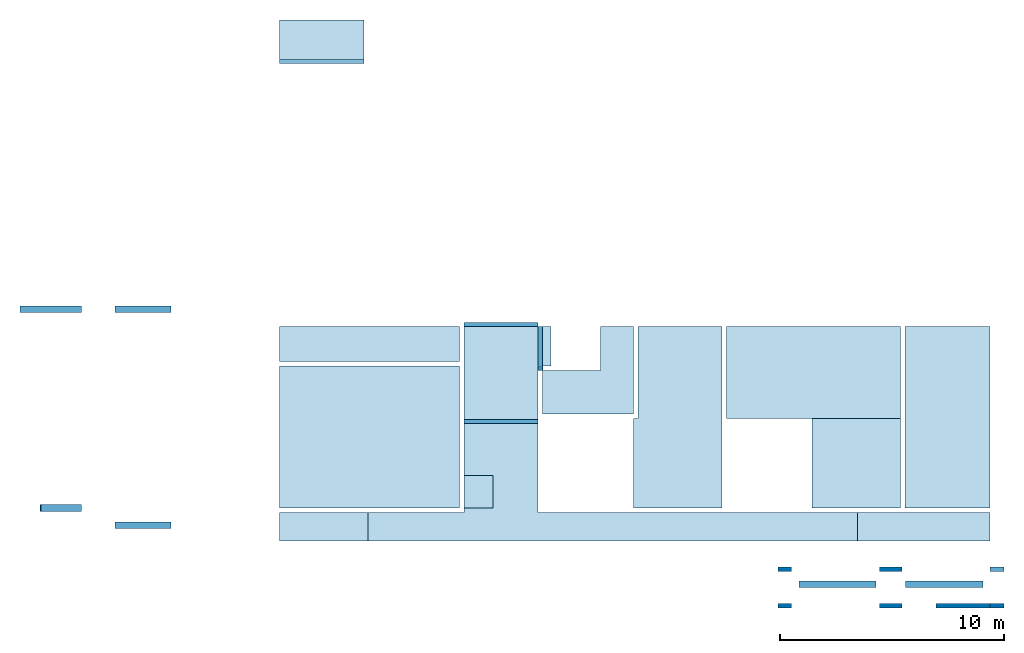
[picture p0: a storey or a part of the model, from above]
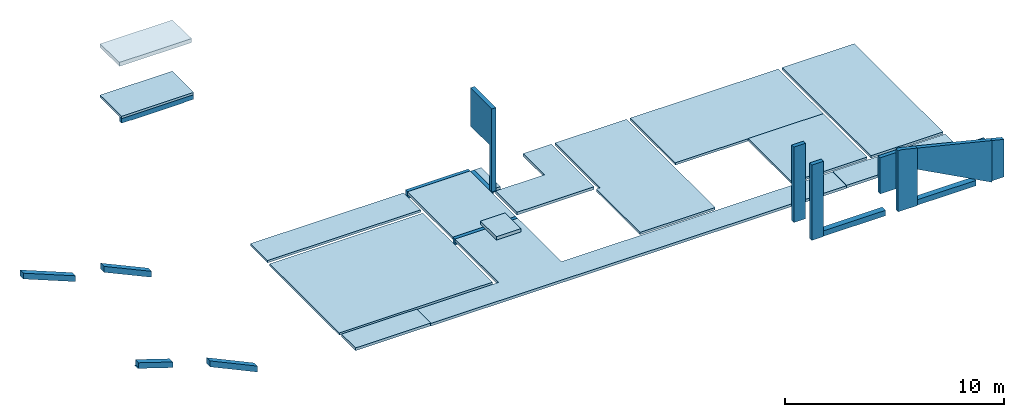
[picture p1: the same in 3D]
Properties of the parts of a building model (IFC2X3)

# File
Description: ViewDefinition [CoordinationView_V2.0]
File name: 20-10
Time: 2021-09-02T08:59:20
Written by: The EXPRESS Data Manager Version 5.02.0100.07 : 28 Aug 2013
Made in: 20200210_1400(x64) - Exporter 20.2.12.1 - Alternate UI 20.2.12.1
Comment: STEP Physical File produced by: The EXPRESS Data Manager Version 5.02.0100.07 : 28 Aug 2013 * Module: EDMstepFileFactory/EDMstandAlone * Creation date: Thu Sep 02 08:59:20 2021 * Host: KAWESQAR * Database: C:\Users\MANONB~1\AppData\Local\Temp\62fa37c4-7dab-49d4-8f40-0b2dbcf1714f\3ce987a9-b15d-487f-94de-988076b2c18d\ifc * Database version: 5507 * Database creation date: Thu Sep 02 08:59:12 2021 * Schema: IFC2X3 * Model: DataRepository.ifc * Model creation date: Thu Sep 02 08:59:13 2021 * Header model: DataRepository.ifc_HeaderModel * Header model creation date: Thu Sep 02 08:59:13 2021 * EDMuser: sdai-user * EDMgroup: sdai-group * License ID and type: 5605 : Permanent license. Expiry date: * EDMstepFileFactory options: 020000

# IfcProject, 20-10
LongName: OPERATION

# IfcSite, Default
RefLatitude: 48, 51, 57, 604064; RefLongitude: 2, 19, 58, 799800; RefElevation: 0 m

# IfcBuilding
Pset_BuildingCommon - NumberOfStoreys: 9
Pset_ProductRequirements - Category: Project Information

# IfcBuildingStorey: Niveau:911002-NIV_nom.topo (9)
Pset_ProductRequirements - Category: Levels
Name | LongName | Elevation (m) | Pset_AirSideSystemInformation, Name = Pset_ProductRequirements, Name
S02 | S02 | -5.05 | Fondations - Vue en plan
S02 | S02 | -4.68 | STR-SS01 Brut
S02 | S02 | -4.62 | STR-SS01 Fini
S01 | S01 | -0.4 | STR-FOND RDC
S01 | S01 | -0.06 | STR-RDC Brut
S01 | S01 | 0 | STR-RDC Fini
01 | 01 | 4.27 | STR-R+1
01 | 01 | 7.55 | STR-R+2
01 | 01 | 10.65 | STR-R+3

# IfcBeam: 16x23ht (2)
In: S01
Type - PredefinedType: BEAM; Material: Béton, coulé sur place gris
Type - Pset_BeamCommon - IsExternal: no; Reference: 16x23ht
Type - Pset_ProductRequirements - Category: Structural Framing
Type - Pset_QuantityTakeOff - Reference: 16x23ht
Type - Pset_ReinforcementBarPitchOfBeam - Reference: 16x23ht
Pset_BeamCommon - Slope: 0 deg; Span: 4.4883 m
Pset_QuantityTakeOff - sets with these values: 2
Name (II-Poutre rectangulaire - Béton:16x23ht:...)
7692531
7692542

# IfcBeam: 16x23ht (9)
In: S01
Type - PredefinedType: BEAM
Type - Pset_BeamCommon - IsExternal: no; Reference: 16x23ht
Type - Pset_ProductRequirements - Category: Structural Framing
Type - Pset_QuantityTakeOff - Reference: 16x23ht
Type - Pset_ReinforcementBarPitchOfBeam - Reference: 16x23ht
Material: Béton, coulé sur place gris
Pset_BeamCommon - Slope: 0 deg
Pset_QuantityTakeOff - sets with these values: 2
Name (II-Poutre rectangulaire - Béton:16x23ht:...) | Span (m)
7692025 | 3.61
7692352 | 3.61
7692365 | 3.335
7692429 | 3.775
7692487 | 3.61
7692498 | 3.61
7692507 | 3.61
7692520 | 3.61
7693165 | 11.4065

# IfcBeam: 16x30ht, II-Poutre rectangulaire - Béton:16x30ht:7629297
In: S01
Type - PredefinedType: BEAM
Type - Pset_BeamCommon - IsExternal: no; Reference: 16x30ht
Type - Pset_ProductRequirements - Category: Structural Framing
Type - Pset_QuantityTakeOff - Reference: 16x30ht
Type - Pset_ReinforcementBarPitchOfBeam - Reference: 16x30ht
Material: Béton, coulé sur place gris
Pset_BeamCommon - Slope: 0 deg; Span: 2.2 m
Pset_QuantityTakeOff - sets with these values: 2

# IfcBeam: 18x15ht (2)
In: S01
Type - PredefinedType: BEAM
Type - Pset_BeamCommon - IsExternal: no; Reference: 18x15ht
Type - Pset_ProductRequirements - Category: Structural Framing
Type - Pset_QuantityTakeOff - Reference: 18x15ht
Type - Pset_ReinforcementBarPitchOfBeam - Reference: 18x15ht
Material: Béton, coulé sur place gris
Pset_BeamCommon - Slope: 0 deg
Pset_QuantityTakeOff - sets with these values: 2
Name (II-Poutre rectangulaire - Béton:18x15ht:...) | Span (m)
8502568 | 5.2
8502663 | 0.2325

# IfcBeam: 18x35ht (5)
Type - PredefinedType: BEAM
Type - Pset_BeamCommon - IsExternal: no; Reference: 18x35ht
Type - Pset_ProductRequirements - Category: Structural Framing
Type - Pset_QuantityTakeOff - Reference: 18x35ht
Type - Pset_ReinforcementBarPitchOfBeam - Reference: 18x35ht
Material: Béton, coulé sur place gris
Pset_BeamCommon - Slope: 0 deg
Pset_QuantityTakeOff - sets with these values: 2
Name (II-Poutre rectangulaire - Béton:18x35ht:...) | In | Span (m)
7599094 | S02 | 3.51
7617457 | S01 | 1.54703
7618718 | S01 | 1.17067
7618989 | S01 | 0.495
7619958 | S01 | 1.886

# IfcBeam: 18x40ht (2)
In: S02
Type - PredefinedType: BEAM
Type - Pset_BeamCommon - IsExternal: no; Reference: 18x40ht
Type - Pset_ProductRequirements - Category: Structural Framing
Type - Pset_QuantityTakeOff - Reference: 18x40ht
Type - Pset_ReinforcementBarPitchOfBeam - Reference: 18x40ht
Material: Béton, coulé sur place gris
Pset_BeamCommon - Slope: 0 deg
Pset_QuantityTakeOff - sets with these values: 2
Name (II-Poutre rectangulaire - Béton:18x40ht:...) | Span (m)
7599215 | 3.31
8826257 | 4.05

# IfcBeam: 20x118ht, II-Poutre rectangulaire - Béton:20x118ht:8638301
In: S01
Type - PredefinedType: BEAM
Type - Pset_BeamCommon - IsExternal: no; Reference: 20x118ht
Type - Pset_ProductRequirements - Category: Structural Framing
Type - Pset_QuantityTakeOff - Reference: 20x118ht
Type - Pset_ReinforcementBarPitchOfBeam - Reference: 20x118ht
Material: Béton, coulé sur place gris
Pset_BeamCommon - Slope: 0 deg; Span: 1.62398 m
Pset_QuantityTakeOff - sets with these values: 2

# IfcBeam: 20x132ht (3)
In: S01
Type - PredefinedType: BEAM
Type - Pset_BeamCommon - IsExternal: no; Reference: 20x132ht
Type - Pset_ProductRequirements - Category: Structural Framing
Type - Pset_QuantityTakeOff - Reference: 20x132ht
Type - Pset_ReinforcementBarPitchOfBeam - Reference: 20x132ht
Material: Béton, coulé sur place gris
Pset_QuantityTakeOff - sets with these values: 2
Name (II-Poutre rectangulaire - Béton:20x132ht:...) | Span (m) | Slope (deg)
8632984 | 5.15244 | 28.0725
8637588 | 4.48138 | 28.1295
8639667 | 5.15882 | 28.0725

# IfcBeam: 20x140ht (2)
In: S01
Type - PredefinedType: BEAM
Type - Pset_BeamCommon - IsExternal: no; Reference: 20x140ht
Type - Pset_ProductRequirements - Category: Structural Framing
Type - Pset_QuantityTakeOff - Reference: 20x140ht
Type - Pset_ReinforcementBarPitchOfBeam - Reference: 20x140ht
Material: Béton, coulé sur place gris
Pset_BeamCommon - Slope: 0 deg; Span: 0.621176 m
Pset_QuantityTakeOff - sets with these values: 2
Name (II-Poutre rectangulaire - Béton:20x140ht:...)
8636644
8639673

# IfcBeam: 20x30ht, II-Poutre rectangulaire - Béton:20x30ht:7633287
In: S01
Type - PredefinedType: BEAM
Type - Pset_BeamCommon - IsExternal: no; Reference: 20x30ht
Type - Pset_ProductRequirements - Category: Structural Framing
Type - Pset_QuantityTakeOff - Reference: 20x30ht
Type - Pset_ReinforcementBarPitchOfBeam - Reference: 20x30ht
Material: Béton, coulé sur place gris
Pset_BeamCommon - Slope: 0 deg; Span: 0.59 m
Pset_QuantityTakeOff - sets with these values: 2

# IfcBeam: 20x40ht (13)
Type - PredefinedType: BEAM
Type - Pset_BeamCommon - IsExternal: no; Reference: 20x40ht
Type - Pset_ProductRequirements - Category: Structural Framing
Type - Pset_QuantityTakeOff - Reference: 20x40ht
Type - Pset_ReinforcementBarPitchOfBeam - Reference: 20x40ht
Material: Béton, coulé sur place gris
Pset_BeamCommon - Slope: 0 deg
Pset_QuantityTakeOff - sets with these values: 2
Name (II-Poutre rectangulaire - Béton:20x40ht:...) | In | Span (m)
7574183 | S01 | 3.52
7591529 | S01 | 3.61
7612690 | S01 | 1.6451
7617019 | S01 | 3.65
7617021 | S01 | 3.758
7617295 | S01 | 3.82
7617297 | S01 | 3.758
7618058 | S01 | 2.55723
7618201 | S01 | 3.698
7618258 | S01 | 9.49483
7631757 | S02 | 1.95
8399992 | S01 | 3.532
8503061 | S01 | 3.51

# IfcBeam: 20x50ht (2)
In: S01
Type - PredefinedType: BEAM
Type - Pset_BeamCommon - IsExternal: no; Reference: 20x50ht
Type - Pset_ProductRequirements - Category: Structural Framing
Type - Pset_QuantityTakeOff - Reference: 20x50ht
Type - Pset_ReinforcementBarPitchOfBeam - Reference: 20x50ht
Material: Béton, coulé sur place gris
Pset_BeamCommon - Slope: 0 deg
Pset_QuantityTakeOff - sets with these values: 2
Name (II-Poutre rectangulaire - Béton:20x50ht:...) | Span (m)
8826786 | 3.9
8826904 | 2.17195

# IfcBeam: 20x55ht (2)
In: S01
Type - PredefinedType: BEAM; Material: Béton, coulé sur place gris
Type - Pset_BeamCommon - IsExternal: no; Reference: 20x55ht
Type - Pset_ProductRequirements - Category: Structural Framing
Type - Pset_QuantityTakeOff - Reference: 20x55ht
Type - Pset_ReinforcementBarPitchOfBeam - Reference: 20x55ht
Pset_BeamCommon - Slope: 0 deg; Span: 3.29967 m
Pset_QuantityTakeOff - sets with these values: 2
Name (II-Poutre rectangulaire - Béton:20x55ht:...)
7572684
7572694

# IfcBeam: 20x55ht (6)
In: S01
Type - PredefinedType: BEAM
Type - Pset_BeamCommon - IsExternal: no; Reference: 20x55ht
Type - Pset_ProductRequirements - Category: Structural Framing
Type - Pset_QuantityTakeOff - Reference: 20x55ht
Type - Pset_ReinforcementBarPitchOfBeam - Reference: 20x55ht
Material: Béton, coulé sur place gris
Pset_BeamCommon - Slope: 0 deg
Pset_QuantityTakeOff - sets with these values: 2
Name (II-Poutre rectangulaire - Béton:20x55ht:...) | Span (m)
7571483 | 3.49167
7572730 | 1.54167
7572750 | 1.54167
7572760 | 1.54167
7581678 | 1.54167
7642646 | 1.44167

# IfcBeam: 20x56ht, II-Poutre rectangulaire - Béton:20x56ht:7572720
In: S01
Type - PredefinedType: BEAM
Type - Pset_BeamCommon - IsExternal: no; Reference: 20x56ht
Type - Pset_ProductRequirements - Category: Structural Framing
Type - Pset_QuantityTakeOff - Reference: 20x56ht
Type - Pset_ReinforcementBarPitchOfBeam - Reference: 20x56ht
Material: Béton, coulé sur place gris
Pset_BeamCommon - Slope: 0 deg; Span: 8.20316 m
Pset_QuantityTakeOff - sets with these values: 2

# IfcBeam: 20x62ht, II-Poutre rectangulaire - Béton:20x62ht:7572740
In: S01
Type - PredefinedType: BEAM
Type - Pset_BeamCommon - IsExternal: no; Reference: 20x62ht
Type - Pset_ProductRequirements - Category: Structural Framing
Type - Pset_QuantityTakeOff - Reference: 20x62ht
Type - Pset_ReinforcementBarPitchOfBeam - Reference: 20x62ht
Material: Béton, coulé sur place gris
Pset_BeamCommon - Slope: 0 deg; Span: 8.30316 m
Pset_QuantityTakeOff - sets with these values: 2

# IfcBeam: 20x90ht, II-Poutre rectangulaire - Béton:20x90ht:7620301
In: S01
Type - PredefinedType: BEAM
Type - Pset_BeamCommon - IsExternal: no; Reference: 20x90ht
Type - Pset_ProductRequirements - Category: Structural Framing
Type - Pset_QuantityTakeOff - Reference: 20x90ht
Type - Pset_ReinforcementBarPitchOfBeam - Reference: 20x90ht
Material: Béton, coulé sur place gris
Pset_BeamCommon - Slope: 0 deg; Span: 8.19316 m
Pset_QuantityTakeOff - sets with these values: 2

# IfcBeam: 22x30ht, II-Poutre rectangulaire - Béton:22x30ht:7593265
In: S01
Type - PredefinedType: BEAM; Material: Béton, coulé sur place gris
Type - Pset_BeamCommon - IsExternal: no; Reference: 22x30ht
Type - Pset_ProductRequirements - Category: Structural Framing
Type - Pset_QuantityTakeOff - Reference: 22x30ht
Type - Pset_ReinforcementBarPitchOfBeam - Reference: 22x30ht
Pset_BeamCommon - Slope: 0 deg; Span: 2 m
Pset_QuantityTakeOff - sets with these values: 2

# IfcBeam: 22x30ht (27)
In: S01
Type - PredefinedType: BEAM
Type - Pset_BeamCommon - IsExternal: no; Reference: 22x30ht
Type - Pset_ProductRequirements - Category: Structural Framing
Type - Pset_QuantityTakeOff - Reference: 22x30ht
Type - Pset_ReinforcementBarPitchOfBeam - Reference: 22x30ht
Material: Béton, coulé sur place gris
Pset_BeamCommon - Slope: 0 deg
Pset_QuantityTakeOff - sets with these values: 2
Name (II-Poutre rectangulaire - Béton:22x30ht:...) | Span (m)
7587745 | 1.27
7587968 | 2
7588278 | 2
7588496 | 8.41316
7593404 | 2
7593542 | 2
7593663 | 1.27
7593817 | 8.30316
7616295 | 1.348
7617360 | 1.238
7629687 | 5.25316
7633593 | 0.47
7633881 | 0.36
7634137 | 1.22
7634286 | 2
7634299 | 2
7634314 | 2
7634327 | 2
7634340 | 2
7634353 | 1.22
7634430 | 8.52315
7634671 | 2.54
7634673 | 2
7634675 | 2
7634677 | 2
7634679 | 2
7634681 | 1.12

# IfcBeam: 25x66.5/100Ht, Poutre_Ai_Variable:25x66.5/100Ht:7585513
In: S01
Type - PredefinedType: BEAM
Type - Pset_BeamCommon - IsExternal: no; Reference: 25x66.5/100Ht
Type - Pset_ProductRequirements - Category: Structural Framing
Type - Pset_QuantityTakeOff - Reference: 25x66.5/100Ht
Type - Pset_ReinforcementBarPitchOfBeam - Reference: 25x66.5/100Ht
Pset_BeamCommon - Slope: 0 deg; Span: 5.695 m
Pset_QuantityTakeOff - sets with these values: 2

# IfcBeam: 25x66/100Ht, Poutre_Ai_Variable:25x66/100Ht:7585440
In: S01
Type - PredefinedType: BEAM
Type - Pset_BeamCommon - IsExternal: no; Reference: 25x66/100Ht
Type - Pset_ProductRequirements - Category: Structural Framing
Type - Pset_QuantityTakeOff - Reference: 25x66/100Ht
Type - Pset_ReinforcementBarPitchOfBeam - Reference: 25x66/100Ht
Pset_BeamCommon - Slope: 0 deg; Span: 5.7915 m
Pset_QuantityTakeOff - sets with these values: 2

# IfcBeam: 30x30ht (8)
In: S02
Type - PredefinedType: BEAM
Type - Pset_BeamCommon - IsExternal: no; Reference: 30x30ht
Type - Pset_ProductRequirements - Category: Structural Framing
Type - Pset_QuantityTakeOff - Reference: 30x30ht
Type - Pset_ReinforcementBarPitchOfBeam - Reference: 30x30ht
Material: Béton, coulé sur place gris
Pset_QuantityTakeOff - sets with these values: 2
Name (II-Poutre rectangulaire - Béton:30x30ht:...) | Slope (deg) | Span (m)
8715014 | 0 | 3.44297
8715320 | 0 | 3.46738
8716602 | 24.7024 | 2.88982
8717387 | 21.9808 | 3.08666
8717692 | 0 | 2.72
8717882 | 18 | 1.9956
8718087 | 25 | 2.89834
8718254 | 16.4686 | 2.92505

# IfcBeam: 36x30ht, II-Poutre rectangulaire - Béton:36x30ht:8716125
In: S01
Type - PredefinedType: BEAM
Type - Pset_BeamCommon - IsExternal: no; Reference: 36x30ht
Type - Pset_ProductRequirements - Category: Structural Framing
Type - Pset_QuantityTakeOff - Reference: 36x30ht
Type - Pset_ReinforcementBarPitchOfBeam - Reference: 36x30ht
Material: Béton, coulé sur place gris
Pset_BeamCommon - Slope: 0 deg; Span: 0.89 m
Pset_QuantityTakeOff - sets with these values: 2

# IfcBeam: 45x30ht (3)
In: S01
Type - PredefinedType: BEAM
Type - Pset_BeamCommon - IsExternal: no; Reference: 45x30ht
Type - Pset_ProductRequirements - Category: Structural Framing
Type - Pset_QuantityTakeOff - Reference: 45x30ht
Type - Pset_ReinforcementBarPitchOfBeam - Reference: 45x30ht
Material: Béton, coulé sur place gris
Pset_BeamCommon - Slope: 0 deg
Pset_QuantityTakeOff - sets with these values: 2
Name (II-Poutre rectangulaire - Béton:45x30ht:...) | Span (m)
8715521 | 1.58184
8715740 | 1.737
8716074 | 3.39816

# IfcBeam: 50x100ht (2)
In: S01
Type - PredefinedType: BEAM
Type - Pset_BeamCommon - IsExternal: no; Reference: 50x100ht
Type - Pset_ProductRequirements - Category: Structural Framing
Type - Pset_QuantityTakeOff - Reference: 50x100ht
Type - Pset_ReinforcementBarPitchOfBeam - Reference: 50x100ht
Material: Béton, coulé sur place gris
Pset_BeamCommon - Slope: 0 deg; Span: 4 m
Pset_QuantityTakeOff - sets with these values: 2
Name (II-Poutre rectangulaire - Béton:50x100ht:...)
7576085
7576991

# IfcBeam: 50x90/100Ht (2)
In: S01
Type - PredefinedType: BEAM
Type - Pset_BeamCommon - IsExternal: no; Reference: 50x90/100Ht
Type - Pset_ProductRequirements - Category: Structural Framing
Type - Pset_QuantityTakeOff - Reference: 50x90/100Ht
Type - Pset_ReinforcementBarPitchOfBeam - Reference: 50x90/100Ht
Pset_BeamCommon - Slope: 0 deg; Span: 4.6633 m
Pset_QuantityTakeOff - sets with these values: 2
Name (Poutre_Ai_Variable:50x90/100Ht:...)
7575710
7576989

# IfcBuildingElementProxy: II_Regards borgnes (5)
In: S02
Type - Material: Béton - Coulé sur place - Béton
Type - Pset_BuildingElementProxyCommon - Reference: II_Regards borgnes
Type - Pset_ProductRequirements - Category: Generic Models
Type - Pset_QuantityTakeOff - Reference: II_Regards borgnes
Pset_BuildingElementProxyCommon - sets with these values: 2
Name (II_Regard borgne:II_Regards borgnes:...)
7672421
7672434
7672905
8828941
8828971

# IfcDistributionPort (6)
Description: Flow; FlowDirection: SOURCEANDSINK
Name | Group
2 x Port_7672416 | M531 1
2 x Port_7672438 | M531 2
2 x Port_8829009 | M531 14

# IfcFlowSegment: Pipe Types:II DEP (3)
In: S02
Pset_DistributionFlowElementCommon - Reference: II DEP; sets with these values: 2
Pset_ElementShading - Roughness: 0.00005 m
Pset_FlowSegmentPipeSegment - InvertElevation: -4.88 m
Pset_ProductRequirements - Category: Pipes
Name (Pipe Types:II DEP:...) | Pset_FlowSegmentDuctSegment, Length (m) = Pset_FlowSegmentPipeSegment, Length (m) | Group
7672416 | 24.0358 | M531 1
7672438 | 32.7956 | M531 2
8829009 | 4.29668 | M531 14

# IfcFooting: Wall Foundation:100x40ht (4)
In: S02
PredefinedType: STRIP_FOOTING; Material: Béton - Coulé sur place - Béton
Pset_ProductRequirements - Category: Structural Foundations
Pset_QuantityTakeOff - Reference: 100x40ht; sets with these values: 3
Name (Wall Foundation:100x40ht:...)
7600112
7600126
8640551
8640759

# IfcFooting: Wall Foundation:190x90ht (4)
In: S02
PredefinedType: STRIP_FOOTING; Material: Béton - Coulé sur place - Béton
Pset_ProductRequirements - Category: Structural Foundations
Pset_QuantityTakeOff - Reference: 190x90ht; sets with these values: 3
Name (Wall Foundation:190x90ht:...)
8500869
8639962
8640098
8640227

# IfcFooting: Wall Foundation:220x100ht, Wall Foundation:220x100ht:7600168
In: S02
PredefinedType: STRIP_FOOTING; Material: Béton - Coulé sur place - Béton
Pset_ProductRequirements - Category: Structural Foundations
Pset_QuantityTakeOff - Reference: 220x100ht; sets with these values: 3

# IfcFooting: Wall Foundation:250x35ht (3)
In: S02
PredefinedType: STRIP_FOOTING; Material: Béton - Coulé sur place - Béton
Pset_ProductRequirements - Category: Structural Foundations
Pset_QuantityTakeOff - Reference: 250x35ht; sets with these values: 3
Name (Wall Foundation:250x35ht:...)
7599897
8825974
8826029

# IfcFooting: Wall Foundation:360x100ht, Wall Foundation:360x100ht:7600098
In: S02
PredefinedType: STRIP_FOOTING; Material: Béton - Coulé sur place - Béton
Pset_ProductRequirements - Category: Structural Foundations
Pset_QuantityTakeOff - Reference: 360x100ht; sets with these values: 3

# IfcFooting: Wall Foundation:40x20ht (2)
In: S02
PredefinedType: STRIP_FOOTING; Material: Béton - Coulé sur place - Béton
Pset_ProductRequirements - Category: Structural Foundations
Pset_QuantityTakeOff - Reference: 40x20ht; sets with these values: 3
Name (Wall Foundation:40x20ht:...)
7605358
8646439

# IfcOpeningElement: Opening (50)
Name | In
Basic Wall:Mur BA - 20cm:8395046 | S02
Basic Wall:Mur BA - 20cm:7560500 | S02 | Pset_ElementShading - Roughness: 0.9144 m; Pset_ProductRequirements - Category: Walls; Pset_QuantityTakeOff - Reference: Mur BA - 20cm; sets with these values: 2
3 x Basic Wall:Mur BA - ASC 35cm:7560565 | S02 | Pset_ElementShading - Roughness: 0.9144 m; Pset_ProductRequirements - Category: Walls; Pset_QuantityTakeOff - Reference: Mur BA - ASC 35cm; sets with these values: 2
Basic Wall:Mur BA - 20cm:7561134 | S02 | Pset_ElementShading - Roughness: 0.9144 m; Pset_ProductRequirements - Category: Walls; Pset_QuantityTakeOff - Reference: Mur BA - 20cm; sets with these values: 2
3 x Basic Wall:Mur BA - 20cm:7561252 | S02 | Pset_ElementShading - Roughness: 0.9144 m; Pset_ProductRequirements - Category: Walls; Pset_QuantityTakeOff - Reference: Mur BA - 20cm; sets with these values: 2
Floor:Dalle BA ép.22:7578940:2 | S01 | Pset_ElementShading - Roughness: 0.9144 m; Pset_ProductRequirements - Category: Floors; Pset_OpeningElementCommon - Reference: Dalle BA ép.22; sets with these values: 2
Floor:Dalle BA ép.20:7581960:2 | S01 | Pset_ElementShading - Roughness: 0.9144 m; Pset_ProductRequirements - Category: Floors; Pset_OpeningElementCommon - Reference: Dalle BA ép.20; sets with these values: 2
2 x Basic Wall:Mur BA - 20cm:7630010 | S01 | Pset_ElementShading - Roughness: 0.9144 m; Pset_ProductRequirements - Category: Walls; Pset_QuantityTakeOff - Reference: Mur BA - 20cm; sets with these values: 2
Basic Wall:Mur BA - 20cm:7635283 | 01
2 x Basic Wall:Mur BA - 20cm:7630014 | S01 | Pset_ElementShading - Roughness: 0.9144 m; Pset_ProductRequirements - Category: Walls; Pset_QuantityTakeOff - Reference: Mur BA - 20cm; sets with these values: 2
2 x Basic Wall:Mur BA - 20cm:7635026 | 01 | Pset_ElementShading - Roughness: 0.9144 m; Pset_ProductRequirements - Category: Walls; Pset_QuantityTakeOff - Reference: Mur BA - 20cm; sets with these values: 2
2 x Basic Wall:Mur BA - 20cm:7635030 | 01 | Pset_ElementShading - Roughness: 0.9144 m; Pset_ProductRequirements - Category: Walls; Pset_QuantityTakeOff - Reference: Mur BA - 20cm; sets with these values: 2
Basic Wall:Mur BA - 20cm:7635277 | 01 | Pset_ElementShading - Roughness: 0.9144 m; Pset_ProductRequirements - Category: Walls; Pset_QuantityTakeOff - Reference: Mur BA - 20cm; sets with these values: 2
2 x Basic Wall:Mur BA - 20cm:7635281 | 01 | Pset_ElementShading - Roughness: 0.9144 m; Pset_ProductRequirements - Category: Walls; Pset_QuantityTakeOff - Reference: Mur BA - 20cm; sets with these values: 2
2 x Basic Wall:Mur BA - 20cm:7554130 | S02
Basic Wall:Mur BA - 20cm:7554411 | S02
Basic Wall:Mur BA - 22cm:7554627 | S02
Basic Wall:Mur BA - 20cm:7556376 | S02
Basic Wall:Mur BA - 20cm:7635279 | 01
2 x Basic Wall:Mur BA - 20cm:7556537 | S02
Basic Wall:Mur BA - 20cm:7556761 | S02
Basic Wall:Mur BA - 20cm:7561134 | S02
Basic Wall:Mur BA - 20cm:7561353 | S02
2 x Basic Wall:Mur BA - 20cm:7570271 | S02
Basic Wall:Mur BA - 20cm:7576279 | S02
4 x Basic Wall:Mur BA - 20cm:7576843 | S02
4 x Basic Wall:Mur BA - 20cm:7577137 | S02
Basic Wall:Mur BA - 20cm:7630012 | S01
Basic Wall:Mur BA - 20cm:7635032 | 01
Basic Wall:Mur BA - 20cm:7630016 | S01
Basic Wall:Mur BA - 20cm:7632461 | S02
Basic Wall:Mur BA - 20cm:7635028 | 01

# IfcSlab: 100x100x30ht, M_Base-Rectangulaire:100x100x30ht:7618499
In: S01
Type - PredefinedType: FLOOR; Material: Béton - Béton coulé sur place
Type - Pset_ProductRequirements - Category: Structural Foundations
Type - Pset_QuantityTakeOff - Reference: 100x100x30ht
Type - Pset_ReinforcementBarPitchOfSlab - Reference: 100x100x30ht
Type - Pset_SlabCommon - IsExternal: no; Reference: 100x100x30ht
Pset_QuantityTakeOff - sets with these values: 2
Pset_SlabCommon - PitchAngle: 0 deg

# IfcSlab: 100x200x40ht, M_Base-Rectangulaire:100x200x40ht:7591483
In: S01
Type - PredefinedType: FLOOR; Material: Béton - Béton coulé sur place
Type - Pset_ProductRequirements - Category: Structural Foundations
Type - Pset_QuantityTakeOff - Reference: 100x200x40ht
Type - Pset_ReinforcementBarPitchOfSlab - Reference: 100x200x40ht
Type - Pset_SlabCommon - IsExternal: no; Reference: 100x200x40ht
Pset_QuantityTakeOff - sets with these values: 2
Pset_SlabCommon - PitchAngle: 0 deg

# IfcSlab: 130x290x70ht (3)
In: S02
Type - PredefinedType: FLOOR; Material: Béton - Béton coulé sur place
Type - Pset_ProductRequirements - Category: Structural Foundations
Type - Pset_QuantityTakeOff - Reference: 130x290x70ht
Type - Pset_ReinforcementBarPitchOfSlab - Reference: 130x290x70ht
Type - Pset_SlabCommon - IsExternal: no; Reference: 130x290x70ht
Pset_QuantityTakeOff - sets with these values: 2
Pset_SlabCommon - PitchAngle: 0 deg
Name (M_Base-Rectangulaire:130x290x70ht:...)
8667762
8667767
8667770

# IfcSlab: 150x250x55ht (4)
In: S01
Type - PredefinedType: FLOOR; Material: Béton - Béton coulé sur place
Type - Pset_ProductRequirements - Category: Structural Foundations
Type - Pset_QuantityTakeOff - Reference: 150x250x55ht
Type - Pset_ReinforcementBarPitchOfSlab - Reference: 150x250x55ht
Type - Pset_SlabCommon - IsExternal: no; Reference: 150x250x55ht
Pset_QuantityTakeOff - sets with these values: 2
Pset_SlabCommon - PitchAngle: 0 deg
Name (M_Base-Rectangulaire:150x250x55ht:...)
7589254
7590332
7590399
7590401

# IfcSlab: 22x44x289ht, M_Base-Rectangulaire:22x44x289ht:7618133
In: S01
Type - PredefinedType: FLOOR; Material: Béton - Béton coulé sur place
Type - Pset_ProductRequirements - Category: Structural Foundations
Type - Pset_QuantityTakeOff - Reference: 22x44x289ht
Type - Pset_ReinforcementBarPitchOfSlab - Reference: 22x44x289ht
Type - Pset_SlabCommon - IsExternal: no; Reference: 22x44x289ht
Pset_QuantityTakeOff - sets with these values: 2
Pset_SlabCommon - PitchAngle: 0 deg

# IfcSlab: 22x44x340ht, M_Base-Rectangulaire:22x44x340ht:7617506
In: S01
Type - PredefinedType: FLOOR; Material: Béton - Béton coulé sur place
Type - Pset_ProductRequirements - Category: Structural Foundations
Type - Pset_QuantityTakeOff - Reference: 22x44x340ht
Type - Pset_ReinforcementBarPitchOfSlab - Reference: 22x44x340ht
Type - Pset_SlabCommon - IsExternal: no; Reference: 22x44x340ht
Pset_QuantityTakeOff - sets with these values: 2
Pset_SlabCommon - PitchAngle: 0 deg

# IfcSlab: 22x44x400ht, M_Base-Rectangulaire:22x44x400ht:7616187
In: S01
Type - PredefinedType: FLOOR; Material: Béton - Béton coulé sur place
Type - Pset_ProductRequirements - Category: Structural Foundations
Type - Pset_QuantityTakeOff - Reference: 22x44x400ht
Type - Pset_ReinforcementBarPitchOfSlab - Reference: 22x44x400ht
Type - Pset_SlabCommon - IsExternal: no; Reference: 22x44x400ht
Pset_QuantityTakeOff - sets with these values: 2
Pset_SlabCommon - PitchAngle: 0 deg

# IfcSlab: 22x44x455ht, M_Base-Rectangulaire:22x44x455ht:7616234
In: S01
Type - PredefinedType: FLOOR; Material: Béton - Béton coulé sur place
Type - Pset_ProductRequirements - Category: Structural Foundations
Type - Pset_QuantityTakeOff - Reference: 22x44x455ht
Type - Pset_ReinforcementBarPitchOfSlab - Reference: 22x44x455ht
Type - Pset_SlabCommon - IsExternal: no; Reference: 22x44x455ht
Pset_QuantityTakeOff - sets with these values: 2
Pset_SlabCommon - PitchAngle: 0 deg

# IfcSlab: 22x44x515ht, M_Base-Rectangulaire:22x44x515ht:7616066
In: S01
Type - PredefinedType: FLOOR; Material: Béton - Béton coulé sur place
Type - Pset_ProductRequirements - Category: Structural Foundations
Type - Pset_QuantityTakeOff - Reference: 22x44x515ht
Type - Pset_ReinforcementBarPitchOfSlab - Reference: 22x44x515ht
Type - Pset_SlabCommon - IsExternal: no; Reference: 22x44x515ht
Pset_QuantityTakeOff - sets with these values: 2
Pset_SlabCommon - PitchAngle: 0 deg

# IfcSlab: 30x60x252ht, M_Base-Rectangulaire:30x60x252ht:7617988
In: S01
Type - PredefinedType: FLOOR; Material: Béton - Béton coulé sur place
Type - Pset_ProductRequirements - Category: Structural Foundations
Type - Pset_QuantityTakeOff - Reference: 30x60x252ht
Type - Pset_ReinforcementBarPitchOfSlab - Reference: 30x60x252ht
Type - Pset_SlabCommon - IsExternal: no; Reference: 30x60x252ht
Pset_QuantityTakeOff - sets with these values: 2
Pset_SlabCommon - PitchAngle: 0 deg

# IfcSlab: 50x50x289ht, M_Base-Rectangulaire:50x50x289ht:7591576
In: S01
Type - PredefinedType: FLOOR; Material: Béton - Béton coulé sur place
Type - Pset_ProductRequirements - Category: Structural Foundations
Type - Pset_QuantityTakeOff - Reference: 50x50x289ht
Type - Pset_ReinforcementBarPitchOfSlab - Reference: 50x50x289ht
Type - Pset_SlabCommon - IsExternal: no; Reference: 50x50x289ht
Pset_QuantityTakeOff - sets with these values: 2
Pset_SlabCommon - PitchAngle: 0 deg

# IfcSlab: 50x50x340ht, M_Base-Rectangulaire:50x50x340ht:7591750
In: S01
Type - PredefinedType: FLOOR; Material: Béton - Béton coulé sur place
Type - Pset_ProductRequirements - Category: Structural Foundations
Type - Pset_QuantityTakeOff - Reference: 50x50x340ht
Type - Pset_ReinforcementBarPitchOfSlab - Reference: 50x50x340ht
Type - Pset_SlabCommon - IsExternal: no; Reference: 50x50x340ht
Pset_QuantityTakeOff - sets with these values: 2
Pset_SlabCommon - PitchAngle: 0 deg

# IfcSlab: 50x50x38ht (20)
In: S01
Type - PredefinedType: FLOOR; Material: Béton - Béton coulé sur place
Type - Pset_ProductRequirements - Category: Structural Foundations
Type - Pset_QuantityTakeOff - Reference: 50x50x38ht
Type - Pset_ReinforcementBarPitchOfSlab - Reference: 50x50x38ht
Type - Pset_SlabCommon - IsExternal: no; Reference: 50x50x38ht
Pset_QuantityTakeOff - sets with these values: 2
Pset_SlabCommon - PitchAngle: 0 deg
Name (M_Base-Rectangulaire:50x50x38ht:...)
7587050
7587276
7587285
7587296
7587305
7587314
7587325
7587332
7587341
7587350
7587389
7587391
7587393
7587395
7587397
7587399
7587401
7587403
7587405
7587407

# IfcSlab: 50x50x400ht, M_Base-Rectangulaire:50x50x400ht:7587530
In: S01
Type - PredefinedType: FLOOR; Material: Béton - Béton coulé sur place
Type - Pset_ProductRequirements - Category: Structural Foundations
Type - Pset_QuantityTakeOff - Reference: 50x50x400ht
Type - Pset_ReinforcementBarPitchOfSlab - Reference: 50x50x400ht
Type - Pset_SlabCommon - IsExternal: no; Reference: 50x50x400ht
Pset_QuantityTakeOff - sets with these values: 2
Pset_SlabCommon - PitchAngle: 0 deg

# IfcSlab: 50x50x455ht, M_Base-Rectangulaire:50x50x455ht:7591741
In: S01
Type - PredefinedType: FLOOR; Material: Béton - Béton coulé sur place
Type - Pset_ProductRequirements - Category: Structural Foundations
Type - Pset_QuantityTakeOff - Reference: 50x50x455ht
Type - Pset_ReinforcementBarPitchOfSlab - Reference: 50x50x455ht
Type - Pset_SlabCommon - IsExternal: no; Reference: 50x50x455ht
Pset_QuantityTakeOff - sets with these values: 2
Pset_SlabCommon - PitchAngle: 0 deg

# IfcSlab: 50x50x515ht, M_Base-Rectangulaire:50x50x515ht:7587519
In: S01
Type - PredefinedType: FLOOR; Material: Béton - Béton coulé sur place
Type - Pset_ProductRequirements - Category: Structural Foundations
Type - Pset_QuantityTakeOff - Reference: 50x50x515ht
Type - Pset_ReinforcementBarPitchOfSlab - Reference: 50x50x515ht
Type - Pset_SlabCommon - IsExternal: no; Reference: 50x50x515ht
Pset_QuantityTakeOff - sets with these values: 2
Pset_SlabCommon - PitchAngle: 0 deg

# IfcSlab: Floor:Dallage ép.13cm (10)
In: S02
Type - PredefinedType: FLOOR; Material: Sol par défaut 0.13 m
Type - Pset_ElementShading - Roughness: 0.9144 m
Type - Pset_ProductRequirements - Category: Floors
Type - Pset_QuantityTakeOff - Reference: Dallage ép.13cm
Type - Pset_ReinforcementBarPitchOfSlab - Reference: Dallage ép.13cm
Type - Pset_SlabCommon - IsExternal: no; Reference: Dallage ép.13cm
Pset_QuantityTakeOff - sets with these values: 2
Pset_SlabCommon - LoadBearing: yes; PitchAngle: 0 deg
Name (Floor:Dallage ép.13cm:...)
7626354
7627321
7627368
7627979
7628752
7628831
7628871
7628914
7629007
8826478

# IfcSlab: Floor:Dalle BA pente ép.18mini, Floor:Dalle BA pente ép.18mini:8826633
In: S02
Type - PredefinedType: FLOOR; Material: Sol par défaut 0.18 m
Type - Pset_ElementShading - Roughness: 0.9144 m
Type - Pset_ProductRequirements - Category: Floors
Type - Pset_QuantityTakeOff - Reference: Dalle BA pente ép.18mini
Type - Pset_ReinforcementBarPitchOfSlab - Reference: Dalle BA pente ép.18mini
Type - Pset_SlabCommon - IsExternal: no; Reference: Dalle BA pente ép.18mini
Pset_QuantityTakeOff - sets with these values: 2
Pset_SlabCommon - IsExternal: yes; LoadBearing: yes; PitchAngle: 0 deg

# IfcSlab: Floor:Dalle BA ép.16, Floor:Dalle BA ép.16:7580221
In: S01
Type - PredefinedType: FLOOR; Material: Sol par défaut 0.16 m
Type - Pset_ElementShading - Roughness: 0.9144 m
Type - Pset_ProductRequirements - Category: Floors
Type - Pset_QuantityTakeOff - Reference: Dalle BA ép.16
Type - Pset_ReinforcementBarPitchOfSlab - Reference: Dalle BA ép.16
Type - Pset_SlabCommon - IsExternal: no; Reference: Dalle BA ép.16
Pset_QuantityTakeOff - sets with these values: 2
Pset_SlabCommon - IsExternal: yes; LoadBearing: yes; PitchAngle: 0 deg

# IfcSlab: Floor:Dalle BA ép.18 (13)
In: S01
Type - PredefinedType: FLOOR; Material: Sol par défaut 0.18 m
Type - Pset_ElementShading - Roughness: 0.9144 m
Type - Pset_ProductRequirements - Category: Floors
Type - Pset_QuantityTakeOff - Reference: Dalle BA ép.18
Type - Pset_ReinforcementBarPitchOfSlab - Reference: Dalle BA ép.18
Type - Pset_SlabCommon - IsExternal: no; Reference: Dalle BA ép.18
Pset_QuantityTakeOff - sets with these values: 2
Pset_SlabCommon - IsExternal: yes; LoadBearing: yes; PitchAngle: 0 deg
Name (Floor:Dalle BA ép.18:...)
7585988
7586419
7586523
7586552
7586577
7586608
7586635
7586664
7586693
7586722
7622235
7623673
7625042

# IfcSlab: Floor:Dalle BA ép.18, Floor:Dalle BA ép.18:7586293
In: S01
Type - PredefinedType: FLOOR
Type - Pset_ElementShading - Roughness: 0.9144 m
Type - Pset_ProductRequirements - Category: Floors
Type - Pset_QuantityTakeOff - Reference: Dalle BA ép.18
Type - Pset_ReinforcementBarPitchOfSlab - Reference: Dalle BA ép.18
Type - Pset_SlabCommon - IsExternal: no; Reference: Dalle BA ép.18
Pset_QuantityTakeOff - sets with these values: 2
Pset_SlabCommon - IsExternal: yes; LoadBearing: yes

# IfcSlab: Floor:Dalle BA ép.19, Floor:Dalle BA ép.19:8500882
In: S02
Type - PredefinedType: FLOOR; Material: Sol par défaut 0.19 m
Type - Pset_ElementShading - Roughness: 0.9144 m
Type - Pset_ProductRequirements - Category: Floors
Type - Pset_QuantityTakeOff - Reference: Dalle BA ép.19
Type - Pset_ReinforcementBarPitchOfSlab - Reference: Dalle BA ép.19
Type - Pset_SlabCommon - IsExternal: no; Reference: Dalle BA ép.19
Pset_QuantityTakeOff - sets with these values: 2
Pset_SlabCommon - IsExternal: yes; LoadBearing: yes; PitchAngle: 0 deg

# IfcSlab: Floor:Dalle BA ép.20 (11)
Type - PredefinedType: FLOOR; Material: Sol par défaut 0.2 m
Type - Pset_ElementShading - Roughness: 0.9144 m
Type - Pset_ProductRequirements - Category: Floors
Type - Pset_QuantityTakeOff - Reference: Dalle BA ép.20
Type - Pset_ReinforcementBarPitchOfSlab - Reference: Dalle BA ép.20
Type - Pset_SlabCommon - IsExternal: no; Reference: Dalle BA ép.20
Pset_QuantityTakeOff - sets with these values: 2
Pset_SlabCommon - IsExternal: yes; LoadBearing: yes; PitchAngle: 0 deg
Name (Floor:Dalle BA ép.20:...) | In
7578823 | S01
7578879 | S01
7579710 | S01
7581325 | S01
7581960 | S01
7582413 | S01
7586377 | S01
7595403 | S01
7621029 | S01
7621495 | S01
7635643 | 01

# IfcSlab: Floor:Dalle BA ép.22 (2)
In: S01
Type - PredefinedType: FLOOR; Material: Sol par défaut 0.22 m
Type - Pset_ElementShading - Roughness: 0.9144 m
Type - Pset_ProductRequirements - Category: Floors
Type - Pset_QuantityTakeOff - Reference: Dalle BA ép.22
Type - Pset_ReinforcementBarPitchOfSlab - Reference: Dalle BA ép.22
Type - Pset_SlabCommon - IsExternal: no; Reference: Dalle BA ép.22
Pset_QuantityTakeOff - sets with these values: 2
Pset_SlabCommon - IsExternal: yes; LoadBearing: yes; PitchAngle: 0 deg
Name (Floor:Dalle BA ép.22:...)
7578940
7583663

# IfcSlab: Floor:Dalle BA ép.23, Floor:Dalle BA ép.23:7586335
In: S01
Type - PredefinedType: FLOOR; Material: Sol par défaut 0.23 m
Type - Pset_ElementShading - Roughness: 0.9144 m
Type - Pset_ProductRequirements - Category: Floors
Type - Pset_QuantityTakeOff - Reference: Dalle BA ép.23
Type - Pset_ReinforcementBarPitchOfSlab - Reference: Dalle BA ép.23
Type - Pset_SlabCommon - IsExternal: no; Reference: Dalle BA ép.23
Pset_QuantityTakeOff - sets with these values: 2
Pset_SlabCommon - IsExternal: yes; LoadBearing: yes; PitchAngle: 0 deg

# IfcSlab: Floor:Dalle BA ép.25 (2)
In: S01
Type - PredefinedType: FLOOR; Material: Sol par défaut 0.25 m
Type - Pset_ElementShading - Roughness: 0.9144 m
Type - Pset_ProductRequirements - Category: Floors
Type - Pset_QuantityTakeOff - Reference: Dalle BA ép.25
Type - Pset_ReinforcementBarPitchOfSlab - Reference: Dalle BA ép.25
Type - Pset_SlabCommon - IsExternal: no; Reference: Dalle BA ép.25
Pset_QuantityTakeOff - sets with these values: 2
Pset_SlabCommon - IsExternal: yes; LoadBearing: yes; PitchAngle: 0 deg
Name (Floor:Dalle BA ép.25:...)
7585941
7595512

# IfcSlab: Floor:Dalle BA ép.60, Floor:Dalle BA ép.60:7631956
In: S01
Type - PredefinedType: FLOOR; Material: Sol par défaut 0.6 m
Type - Pset_ElementShading - Roughness: 0.9144 m
Type - Pset_ProductRequirements - Category: Floors
Type - Pset_QuantityTakeOff - Reference: Dalle BA ép.60
Type - Pset_ReinforcementBarPitchOfSlab - Reference: Dalle BA ép.60
Type - Pset_SlabCommon - IsExternal: no; Reference: Dalle BA ép.60
Pset_QuantityTakeOff - sets with these values: 2
Pset_SlabCommon - IsExternal: yes; LoadBearing: yes; PitchAngle: 0 deg

# IfcSlab: Floor:Dalle portée ép.15cm (6)
In: S02
Type - PredefinedType: FLOOR; Material: Sol par défaut 0.15 m
Type - Pset_ElementShading - Roughness: 0.9144 m
Type - Pset_ProductRequirements - Category: Floors
Type - Pset_QuantityTakeOff - Reference: Dalle portée ép.15cm
Type - Pset_ReinforcementBarPitchOfSlab - Reference: Dalle portée ép.15cm
Type - Pset_SlabCommon - IsExternal: no; Reference: Dalle portée ép.15cm
Pset_QuantityTakeOff - sets with these values: 2
Pset_SlabCommon - LoadBearing: yes; PitchAngle: 0 deg
Name (Floor:Dalle portée ép.15cm:...)
7626544
7626779
7628963
7631344
8399965
8400015

# IfcSlab: Foundation Slab:Radier 40cm, Foundation Slab:Radier 40cm:7601693
In: S02
Type - PredefinedType: BASESLAB; Material: Béton - Coulé sur place - Béton 0.4 m
Type - Pset_ElementShading - Roughness: 0.9144 m
Type - Pset_ProductRequirements - Category: Structural Foundations
Type - Pset_QuantityTakeOff - Reference: Radier 40cm
Type - Pset_ReinforcementBarPitchOfSlab - Reference: Radier 40cm
Type - Pset_SlabCommon - IsExternal: no; Reference: Radier 40cm
Pset_QuantityTakeOff - sets with these values: 2
Pset_SlabCommon - LoadBearing: yes; PitchAngle: 0 deg

# IfcSlab: GB-100x100x37ht, M_Base-Rectangulaire:GB-100x100x37ht:7602297
In: S02
Type - PredefinedType: FLOOR; Material: Béton - Béton coulé sur place
Type - Pset_ProductRequirements - Category: Structural Foundations
Type - Pset_QuantityTakeOff - Reference: GB-100x100x37ht
Type - Pset_ReinforcementBarPitchOfSlab - Reference: GB-100x100x37ht
Type - Pset_SlabCommon - IsExternal: no; Reference: GB-100x100x37ht
Pset_QuantityTakeOff - sets with these values: 2
Pset_SlabCommon - PitchAngle: 0 deg

# IfcSlab: GB-130x100x60ht (2)
In: S02
Type - PredefinedType: FLOOR; Material: Béton - Béton coulé sur place
Type - Pset_ProductRequirements - Category: Structural Foundations
Type - Pset_QuantityTakeOff - Reference: GB-130x100x60ht
Type - Pset_ReinforcementBarPitchOfSlab - Reference: GB-130x100x60ht
Type - Pset_SlabCommon - IsExternal: no; Reference: GB-130x100x60ht
Pset_QuantityTakeOff - sets with these values: 2
Pset_SlabCommon - PitchAngle: 0 deg
Name (M_Base-Rectangulaire:GB-130x100x60ht:...)
7604392
8643197

# IfcSlab: GB-135x230x60ht, M_Base-Rectangulaire:GB-135x230x60ht:8644300
In: S02
Type - PredefinedType: FLOOR; Material: Béton - Béton coulé sur place
Type - Pset_ProductRequirements - Category: Structural Foundations
Type - Pset_QuantityTakeOff - Reference: GB-135x230x60ht
Type - Pset_ReinforcementBarPitchOfSlab - Reference: GB-135x230x60ht
Type - Pset_SlabCommon - IsExternal: no; Reference: GB-135x230x60ht
Pset_QuantityTakeOff - sets with these values: 2
Pset_SlabCommon - PitchAngle: 0 deg

# IfcSlab: GB-40x235x20ht, M_Base-Rectangulaire:GB-40x235x20ht:7605859
In: S02
Type - PredefinedType: FLOOR; Material: Béton - Béton coulé sur place
Type - Pset_ProductRequirements - Category: Structural Foundations
Type - Pset_QuantityTakeOff - Reference: GB-40x235x20ht
Type - Pset_ReinforcementBarPitchOfSlab - Reference: GB-40x235x20ht
Type - Pset_SlabCommon - IsExternal: no; Reference: GB-40x235x20ht
Pset_QuantityTakeOff - sets with these values: 2
Pset_SlabCommon - PitchAngle: 0 deg

# IfcSlab: GB-40x381x40ht, M_Base-Rectangulaire:GB-40x381x40ht:7605691
In: S02
Type - PredefinedType: FLOOR; Material: Béton - Béton coulé sur place
Type - Pset_ProductRequirements - Category: Structural Foundations
Type - Pset_QuantityTakeOff - Reference: GB-40x381x40ht
Type - Pset_ReinforcementBarPitchOfSlab - Reference: GB-40x381x40ht
Type - Pset_SlabCommon - IsExternal: no; Reference: GB-40x381x40ht
Pset_QuantityTakeOff - sets with these values: 2
Pset_SlabCommon - PitchAngle: 0 deg

# IfcSlab: GB-40x76x35ht, M_Base-Rectangulaire:GB-40x76x35ht:8649655
In: S02
Type - PredefinedType: FLOOR; Material: Béton - Béton coulé sur place
Type - Pset_ProductRequirements - Category: Structural Foundations
Type - Pset_QuantityTakeOff - Reference: GB-40x76x35ht
Type - Pset_ReinforcementBarPitchOfSlab - Reference: GB-40x76x35ht
Type - Pset_SlabCommon - IsExternal: no; Reference: GB-40x76x35ht
Pset_QuantityTakeOff - sets with these values: 2
Pset_SlabCommon - PitchAngle: 0 deg

# IfcSlab: GB-70x100x30ht (2)
In: S02
Type - PredefinedType: FLOOR; Material: Béton - Béton coulé sur place
Type - Pset_ProductRequirements - Category: Structural Foundations
Type - Pset_QuantityTakeOff - Reference: GB-70x100x30ht
Type - Pset_ReinforcementBarPitchOfSlab - Reference: GB-70x100x30ht
Type - Pset_SlabCommon - IsExternal: no; Reference: GB-70x100x30ht
Pset_QuantityTakeOff - sets with these values: 2
Pset_SlabCommon - PitchAngle: 0 deg
Name (M_Base-Rectangulaire:GB-70x100x30ht:...)
8643631
8643633

# IfcSlab: GB-930x360x60ht, M_Base-Rectangulaire:GB-930x360x60ht:8641678
In: S02
Type - PredefinedType: FLOOR; Material: Béton - Béton coulé sur place
Type - Pset_ProductRequirements - Category: Structural Foundations
Type - Pset_QuantityTakeOff - Reference: GB-930x360x60ht
Type - Pset_ReinforcementBarPitchOfSlab - Reference: GB-930x360x60ht
Type - Pset_SlabCommon - IsExternal: no; Reference: GB-930x360x60ht
Pset_QuantityTakeOff - sets with these values: 2
Pset_SlabCommon - PitchAngle: 0 deg

# IfcWallStandardCase: Basic Wall:Mur BA - 18cm, Basic Wall:Mur BA - 18cm:7575260
In: S01
Type - PredefinedType: STANDARD; Material: Mur par défaut 0.18 m
Type - Pset_ElementShading - Roughness: 0.9144 m
Type - Pset_ProductRequirements - Category: Walls
Type - Pset_QuantityTakeOff - Reference: Mur BA - 18cm
Type - Pset_ReinforcementBarPitchOfWall - Reference: Mur BA - 18cm
Type - Pset_WallCommon - IsExternal: no; Reference: Mur BA - 18cm
Pset_QuantityTakeOff - sets with these values: 2
Pset_WallCommon - IsExternal: yes; ExtendToStructure: no; LoadBearing: yes

# IfcWallStandardCase: Basic Wall:Mur BA - 20cm (71)
Type - PredefinedType: STANDARD; Material: Mur par défaut 0.2 m
Type - Pset_ElementShading - Roughness: 0.9144 m
Type - Pset_ProductRequirements - Category: Walls
Type - Pset_QuantityTakeOff - Reference: Mur BA - 20cm
Type - Pset_ReinforcementBarPitchOfWall - Reference: Mur BA - 20cm
Type - Pset_WallCommon - Reference: Mur BA - 20cm; IsExternal: no
Pset_QuantityTakeOff - sets with these values: 2
Pset_WallCommon - IsExternal: yes; ExtendToStructure: no; LoadBearing: yes
Name (Basic Wall:Mur BA - 20cm:...) | In
7554130 | S02
7554411 | S02
7556376 | S02
7556537 | S02
7556761 | S02
7559672 | S02
7560148 | S02
7560500 | S02
7561134 | S02
7561252 | S02
7561353 | S02
7561679 | S02
7561681 | S02
7561683 | S02
7570271 | S02
7576279 | S02
7576843 | S02
7577137 | S02
7596995 | S02
7596997 | S02
7597000 | S02
7597002 | S02
7597016 | S02
7597070 | S02
7597088 | S02
7597091 | S02
7597093 | S02
7605047 | S02
7605212 | S02
7606151 | S02
7606304 | S02
7606353 | S02
7615550 | S02
7615732 | S02
7630010 | S01
7630012 | S01
7630014 | S01
7630016 | S01
7630903 | S02
7632461 | S02
7635026 | 01
7635028 | 01
7635030 | 01
7635032 | 01
7635277 | 01
7635279 | 01
7635281 | 01
7635283 | 01
8395046 | S02
8399982 | S02
8500859 | S02
8500867 | S02
8520470 | S02
8636001 | S02
8636114 | S02
8637417 | S02
8637448 | S02
8639663 | S02
8639669 | S02
8639671 | S02
8639675 | S02
8639960 | S02
8640096 | S02
8640225 | S02
8640549 | S02
8641916 | S02
8646437 | S02
8646446 | S02
8667773 | S02
8825584 | S02
8825645 | S02

# IfcWallStandardCase: Basic Wall:Mur BA - 22cm, Basic Wall:Mur BA - 22cm:7554627
In: S02
Type - PredefinedType: STANDARD; Material: Mur par défaut 0.22 m
Type - Pset_ElementShading - Roughness: 0.9144 m
Type - Pset_ProductRequirements - Category: Walls
Type - Pset_QuantityTakeOff - Reference: Mur BA - 22cm
Type - Pset_ReinforcementBarPitchOfWall - Reference: Mur BA - 22cm
Type - Pset_WallCommon - IsExternal: no; Reference: Mur BA - 22cm
Pset_QuantityTakeOff - sets with these values: 2
Pset_WallCommon - IsExternal: yes; ExtendToStructure: no; LoadBearing: yes

# IfcWallStandardCase: Basic Wall:Mur BA - ASC 35cm (2)
In: S02
Type - PredefinedType: STANDARD; Material: Mur par défaut 0.35 m
Type - Pset_ElementShading - Roughness: 0.9144 m
Type - Pset_ProductRequirements - Category: Walls
Type - Pset_QuantityTakeOff - Reference: Mur BA - ASC 35cm
Type - Pset_ReinforcementBarPitchOfWall - Reference: Mur BA - ASC 35cm
Type - Pset_WallCommon - IsExternal: no; Reference: Mur BA - ASC 35cm
Pset_QuantityTakeOff - sets with these values: 2
Pset_WallCommon - IsExternal: yes; ExtendToStructure: no; LoadBearing: yes
Name (Basic Wall:Mur BA - ASC 35cm:...)
7560565
7561677

# IfcWallStandardCase: Basic Wall:Mur BA Contre terre - 20cm (11)
Type - PredefinedType: STANDARD; Material: Mur par défaut 0.2 m
Type - Pset_ElementShading - Roughness: 0.9144 m
Type - Pset_ProductRequirements - Category: Walls
Type - Pset_QuantityTakeOff - Reference: Mur BA Contre terre - 20cm
Type - Pset_ReinforcementBarPitchOfWall - Reference: Mur BA Contre terre - 20cm
Type - Pset_WallCommon - IsExternal: no; Reference: Mur BA Contre terre - 20cm
Pset_QuantityTakeOff - sets with these values: 2
Pset_WallCommon - IsExternal: yes; ExtendToStructure: no; LoadBearing: yes
Name (Basic Wall:Mur BA Contre terre - 20cm:...) | In
8613318 | S01
8614455 | S01
8620376 | S01
8620499 | S01
8620745 | S01
8620971 | S01
8621384 | S01
8639665 | S02
8711633 | S02
8825972 | S02
8826027 | S02

# IfcWallStandardCase: Basic Wall:Mur BA Contre terre - 26cm (7)
In: S02
Type - PredefinedType: STANDARD; Material: Mur par défaut 0.26 m
Type - Pset_ElementShading - Roughness: 0.9144 m
Type - Pset_ProductRequirements - Category: Walls
Type - Pset_QuantityTakeOff - Reference: Mur BA Contre terre - 26cm
Type - Pset_ReinforcementBarPitchOfWall - Reference: Mur BA Contre terre - 26cm
Type - Pset_WallCommon - IsExternal: no; Reference: Mur BA Contre terre - 26cm
Pset_QuantityTakeOff - sets with these values: 2
Pset_WallCommon - IsExternal: yes; ExtendToStructure: no; LoadBearing: yes
Name (Basic Wall:Mur BA Contre terre - 26cm:...)
7559024
7559268
7580139
7597010
7597095
8640619
8640757

# IfcWallStandardCase: Basic Wall:Mur BA Contre terre - 30cm (4)
In: S02
Type - PredefinedType: STANDARD; Material: Mur par défaut 0.3 m
Type - Pset_ElementShading - Roughness: 0.9144 m
Type - Pset_ProductRequirements - Category: Walls
Type - Pset_QuantityTakeOff - Reference: Mur BA Contre terre - 30cm
Type - Pset_ReinforcementBarPitchOfWall - Reference: Mur BA Contre terre - 30cm
Type - Pset_WallCommon - IsExternal: no; Reference: Mur BA Contre terre - 30cm
Pset_QuantityTakeOff - sets with these values: 2
Pset_WallCommon - IsExternal: yes; ExtendToStructure: no; LoadBearing: yes
Name (Basic Wall:Mur BA Contre terre - 30cm:...)
7571254
7574722
7597080
8640889
